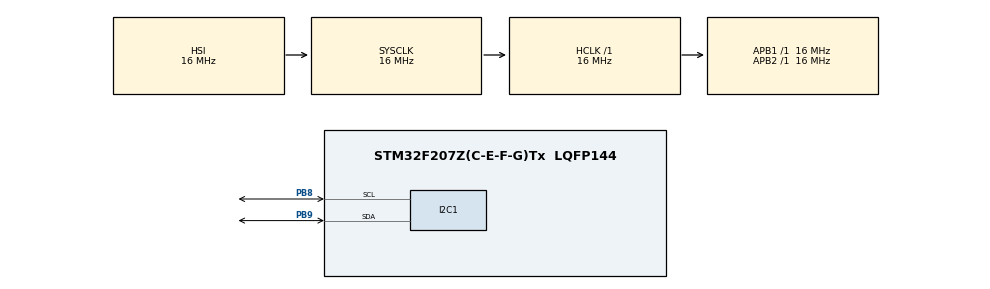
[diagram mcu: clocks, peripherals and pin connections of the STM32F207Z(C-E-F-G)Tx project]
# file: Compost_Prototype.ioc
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Mcu.Family=STM32F2
Mcu.Name=STM32F207Z(C-E-F-G)Tx
Mcu.Package=LQFP144
NVIC.PriorityGroup=NVIC_PRIORITYGROUP_4
PB8.Mode=I2C
PB8.Signal=I2C1_SCL
PB9.Mode=I2C
PB9.Signal=I2C1_SDA
ProjectManager.HeapSize=0x200
ProjectManager.StackSize=0x400
ProjectManager.TargetToolchain=STM32CubeIDE
RCC.48MHZClocksFreq_Value=48000000
RCC.AHBFreq_Value=16000000
RCC.APB1Freq_Value=16000000
RCC.APB2Freq_Value=16000000
RCC.CortexFreq_Value=16000000
RCC.HSE_VALUE=25000000
RCC.HSI_VALUE=16000000
RCC.LSE_VALUE=32768
RCC.SYSCLKFreq_VALUE=16000000
RCC.VCOOutputFreq_Value=192000000
board=custom

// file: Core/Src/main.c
/* USER CODE BEGIN Header */
/**
  ******************************************************************************
  * @file           : main.c
  * @brief          : Main program body
  ******************************************************************************
  * @attention
  *
  * <h2><center>&copy; Copyright (c) 2021 STMicroelectronics.
  * All rights reserved.</center></h2>
  *
  * This software component is licensed by ST under BSD 3-Clause license,
  * the "License"; You may not use this file except in compliance with the
  * License. You may obtain a copy of the License at:
  *                        opensource.org/licenses/BSD-3-Clause
  *
  ******************************************************************************
  */
/* USER CODE END Header */
#include "main.h"

/* USER CODE BEGIN Includes */
#include "LED_UI.h"
#include "I2C_Base.h"
/* USER CODE END Includes */

I2C_HandleTypeDef hi2c1;

void SystemClock_Config(void);
static void MX_GPIO_Init(void);
static void MX_I2C1_Init(void);

int main(void)
{

  /* MCU Configuration--------------------------------------------------------*/

  /* Reset of all peripherals, Initializes the Flash interface and the Systick. */
  HAL_Init();

  /* Configure the system clock */
  SystemClock_Config();

  /* Initialize all configured peripherals */
  MX_GPIO_Init();
  MX_I2C1_Init();

  /* Infinite loop */
  /* USER CODE BEGIN WHILE */
  LED_GPIO_SETUP(); // Resets the LED pins to ensure correct function.

  while (1)
  {
	  LED_Standby();

//	  MCP9808_Chip_Check();

	  /*****TEMP DEVICE ID TEST*****/
	  uint8_t buffer[16];
	  int16_t Raw_Value;

	  buffer[0] = MCP9808_MANUFACTURER_ID;

	  //HAL_StatusTypeDef I2C_Status;

	  if(HAL_I2C_Master_Transmit(&hi2c1, MCP9808_ADR, buffer, 1, HAL_MAX_DELAY) != HAL_OK) { // need to set a sensible delay at some point
		  return 0;
	  }

	  if (HAL_I2C_Master_Receive(&hi2c1, MCP9808_ADR, buffer, 2, HAL_MAX_DELAY) != HAL_OK){
		  return 0; // set up proper error handling
	  }

	  Raw_Value = ((int16_t)buffer[0]) | (buffer[1]);

	  HAL_Delay(500);
	  /*****TEMP DEVICE ID TEST*****/

    /* USER CODE END WHILE */
  }
}

void SystemClock_Config(void)
{
  RCC_OscInitTypeDef RCC_OscInitStruct = {0};
  RCC_ClkInitTypeDef RCC_ClkInitStruct = {0};

  /** Initializes the RCC Oscillators according to the specified parameters
  * in the RCC_OscInitTypeDef structure.
  */
  RCC_OscInitStruct.OscillatorType = RCC_OSCILLATORTYPE_HSI;
  RCC_OscInitStruct.HSIState = RCC_HSI_ON;
  RCC_OscInitStruct.HSICalibrationValue = RCC_HSICALIBRATION_DEFAULT;
  RCC_OscInitStruct.PLL.PLLState = RCC_PLL_NONE;
  if (HAL_RCC_OscConfig(&RCC_OscInitStruct) != HAL_OK)
  {
    Error_Handler();
  }
  /** Initializes the CPU, AHB and APB buses clocks
  */
  RCC_ClkInitStruct.ClockType = RCC_CLOCKTYPE_HCLK|RCC_CLOCKTYPE_SYSCLK
                              |RCC_CLOCKTYPE_PCLK1|RCC_CLOCKTYPE_PCLK2;
  RCC_ClkInitStruct.SYSCLKSource = RCC_SYSCLKSOURCE_HSI;
  RCC_ClkInitStruct.AHBCLKDivider = RCC_SYSCLK_DIV1;
  RCC_ClkInitStruct.APB1CLKDivider = RCC_HCLK_DIV1;
  RCC_ClkInitStruct.APB2CLKDivider = RCC_HCLK_DIV1;

  if (HAL_RCC_ClockConfig(&RCC_ClkInitStruct, FLASH_LATENCY_0) != HAL_OK)
  {
    Error_Handler();
  }
}

static void MX_I2C1_Init(void)
{

  hi2c1.Instance = I2C1;
  hi2c1.Init.ClockSpeed = 100000;
  hi2c1.Init.DutyCycle = I2C_DUTYCYCLE_2;
  hi2c1.Init.OwnAddress1 = 0;
  hi2c1.Init.AddressingMode = I2C_ADDRESSINGMODE_7BIT;
  hi2c1.Init.DualAddressMode = I2C_DUALADDRESS_DISABLE;
  hi2c1.Init.OwnAddress2 = 0;
  hi2c1.Init.GeneralCallMode = I2C_GENERALCALL_DISABLE;
  hi2c1.Init.NoStretchMode = I2C_NOSTRETCH_DISABLE;
  if (HAL_I2C_Init(&hi2c1) != HAL_OK)
  {
    Error_Handler();
  }
  /* USER CODE BEGIN I2C1_Init 2 */
  I2C_Handler_Set(hi2c1);
  /* USER CODE END I2C1_Init 2 */

}

static void MX_GPIO_Init(void)
{
  GPIO_InitTypeDef GPIO_InitStruct = {0};

  /* GPIO Ports Clock Enable */
  __HAL_RCC_GPIOB_CLK_ENABLE();

  /*Configure GPIO pin Output Level */
  HAL_GPIO_WritePin(GPIOB, LED1_Pin|LED3_Pin|LED2_Pin, GPIO_PIN_RESET);

  /*Configure GPIO pins : LED1_Pin LED3_Pin LED2_Pin */
  GPIO_InitStruct.Pin = LED1_Pin|LED3_Pin|LED2_Pin;
  GPIO_InitStruct.Mode = GPIO_MODE_OUTPUT_PP;
  GPIO_InitStruct.Pull = GPIO_NOPULL;
  GPIO_InitStruct.Speed = GPIO_SPEED_FREQ_LOW;
  HAL_GPIO_Init(GPIOB, &GPIO_InitStruct);

}

void Error_Handler(void)
{
  __disable_irq();
  while (1)
  {
  }
}

/************************ (C) COPYRIGHT STMicroelectronics *****END OF FILE****/
